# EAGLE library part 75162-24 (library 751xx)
75xxx DEVICE

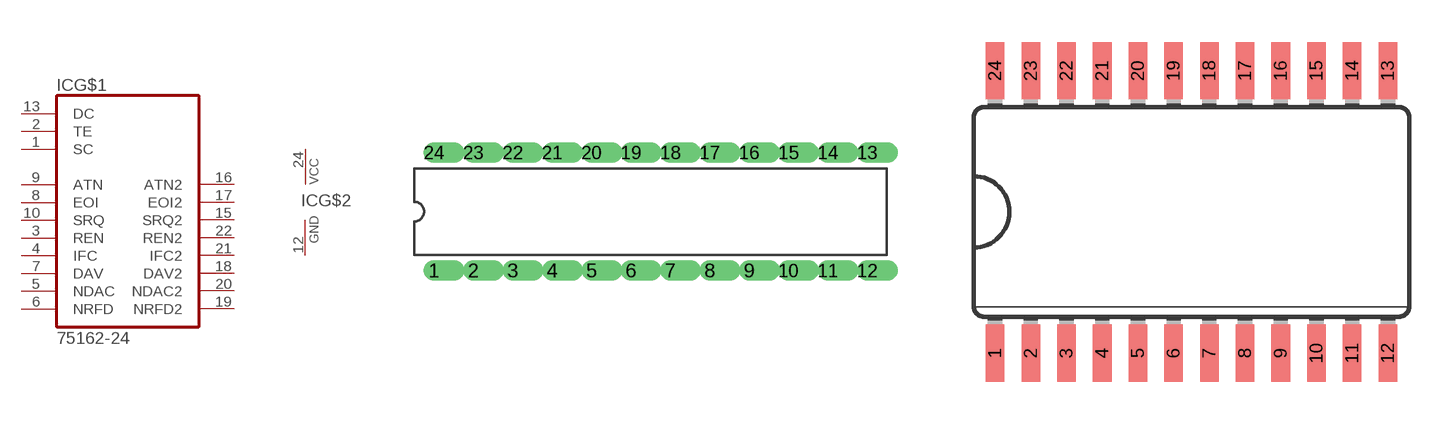
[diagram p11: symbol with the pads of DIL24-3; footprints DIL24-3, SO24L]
Designator prefix IC; gates G$1=75162-24 G$2=PWRN

## 75162-24P  [DIL24-3]
1  G$1:SC  in
2  G$1:TE  in
3  G$1:REN
4  G$1:IFC
5  G$1:NDAC
6  G$1:NRFD
7  G$1:DAV
8  G$1:EOI
9  G$1:ATN
10  G$1:SRQ
11  G$1:NC11  nc
12  G$2:GND  pwr
13  G$1:DC  in
14  G$1:NC14  nc
15  G$1:SRQ2
16  G$1:ATN2
17  G$1:EOI2
18  G$1:DAV2
19  G$1:NRFD2
20  G$1:NDAC2
21  G$1:IFC2
22  G$1:REN2
23  G$1:NC  nc
24  G$2:VCC  pwr

## 75162-24SO  [SO24L]
Pads as for DIL24-3

## Footprint DIL24-3 (pad centres in mm)
Dual In Line 0.3 inch
drill 0.813 offset: 1 -12.7,-3.81; 2 -10.16,-3.81; 3 -7.62,-3.81; 4 -5.08,-3.81; 5 -2.54,-3.81; 6 0,-3.81; 7 2.54,-3.81; 8 5.08,-3.81; 9 7.62,-3.81; 10 10.16,-3.81; 11 12.7,-3.81; 12 15.24,-3.81; 13 15.24,3.81; 14 12.7,3.81; 15 10.16,3.81; 16 7.62,3.81; 17 5.08,3.81; 18 2.54,3.81; 19 0,3.81; 20 -2.54,3.81; 21 -5.08,3.81; 22 -7.62,3.81; 23 -10.16,3.81; 24 -12.7,3.81

## Footprint SO24L (pad centres in mm)
Small Outline package large
smd 0.66 x 2.032: 1 -6.985,-5.029; 2 -5.715,-5.029; 3 -4.445,-5.029; 4 -3.175,-5.029; 5 -1.905,-5.029; 6 -0.635,-5.029; 7 0.635,-5.029; 8 1.905,-5.029; 9 3.175,-5.029; 10 4.445,-5.029; 11 5.715,-5.029; 12 6.985,-5.029; 13 6.985,5.029; 14 5.715,5.029; 15 4.445,5.029; 16 3.175,5.029; 17 1.905,5.029; 18 0.635,5.029; 19 -0.635,5.029; 20 -1.905,5.029; 21 -3.175,5.029; 22 -4.445,5.029; 23 -5.715,5.029; 24 -6.985,5.029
